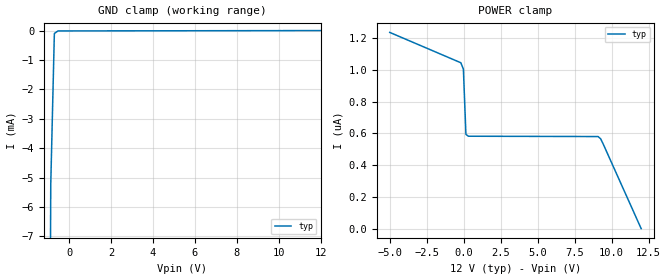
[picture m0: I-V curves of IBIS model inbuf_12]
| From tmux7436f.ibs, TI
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| inbuf_12
[Model]   inbuf_12
Model_type   Input
Vinl = 0.8
Vinh = 1.3
|   typ   min   max
C_comp   6.362683e-13   NA   NA
[Voltage Range]   12   NA   NA
[Temperature Range]   27   NA   NA
[Power Clamp Reference]   12   NA   NA
[GND Clamp Reference]   0   NA   NA
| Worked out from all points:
|   GND clamp passes 1 mA (typ) near -0.74 V on its own axis
[GND Clamp]
|   Voltage   I(typ)   I(min)   I(max)
-5V       -1.962A    NA         NA
-1.051V   -34.12mA   NA         NA
-878.8mV  -5.233mA   NA         NA
-707.1mV  -98.32uA   NA         NA
-535.4mV  -10.94uA   NA         NA
12V       972.6nA    NA         NA
[POWER Clamp]
|   Voltage   I(typ)   I(min)   I(max)
-5V       1.235uA    NA         NA
-191.9mV  1.044uA    NA         NA
-20.2mV   1.004uA    NA         NA
151.5mV   593.1nA    NA         NA
323.2mV   581.6nA    NA         NA
9.081V    579.6nA    NA         NA
9.253V    566.1nA    NA         NA
9.424V    534.2nA    NA         NA
12V       -75.95pA   NA         NA
